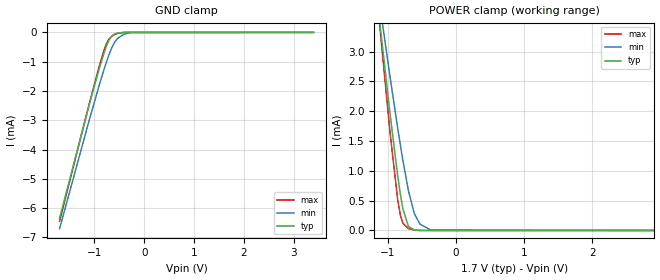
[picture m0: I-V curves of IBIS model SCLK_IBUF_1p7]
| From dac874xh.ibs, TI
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|   SCLK_IBUF_1p7 Model
[Model]   SCLK_IBUF_1p7
Model_type   Input
Vinl = 0.51
Vinh = 1.19
|   typ   min   max
C_comp   1.31128E-13  2.39925E-14  2.16304E-13
| Where nom  PVT is Nominal Process, 1.7V, 27C
|   Fast PVT is Strong Process,  1.701V, -40C
|   Slow PVT is Weak Process,   1.699V, 150C
[Model spec]
|subparameter
Vinl   0.51   0.5097   0.5103
Vinh   1.19   1.1893   1.1907
[Voltage Range]   1.7   1.699   1.701
[Temperature Range]   27   150   -40
[Power Clamp Reference]   1.7   1.699   1.701
[GND Clamp Reference]   0   0   0
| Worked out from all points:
|   GND clamp passes 1 mA (typ) near -0.86 V on its own axis
|   POWER clamp passes 1 mA (typ) near -0.87 V on its own axis
[GND Clamp]
|   Voltage   I(typ)   I(min)   I(max)
-1.7V     -6.346mA   -6.703mA   -6.448mA
-1.108V   -2.489mA   -3.012mA   -2.457mA
-909.5mV  -1.269mA   -1.833mA   -1.19mA
-802.4mV  -672.9uA   -1.237mA   -580uA
-761.6mV  -474.1uA   -1.023mA   -391.4uA
-710.6mV  -269.6uA   -773uA     -230.7uA
-649.4mV  -118.9uA   -512uA     -132.6uA
-593.3mV  -55.04uA   -328.8uA   -72.77uA
-527mV    -18.35uA   -191.5uA   -25.83uA
-399.5mV  -716.4nA   -56.52uA   -733.1nA
-272mV    0A         -5.142uA   0A
3.4V      0A         0A         0A
[POWER Clamp]
|   Voltage   I(typ)   I(min)   I(max)
-1.7V     9.733mA    8.663mA    10.85mA
-1.124V   3.512mA    3.807mA    3.46mA
-1.108V   3.353mA    3.682mA    3.272mA
-970.7mV  1.958mA    2.578mA    1.643mA
-858.5mV  921.5uA    1.719mA    518.9uA
-817.7mV  598.5uA    1.423mA    250.4uA
-782mV    362.4uA    1.175mA    123.4uA
-700.4mV  68.48uA    666.9uA    31.59uA
-613.7mV  7.599uA    281.7uA    4.809uA
-532.1mV  718.8nA    106.6uA    389.6nA
-368.9mV  0A         6.618uA    0A
3.4V      0A         0A         0A
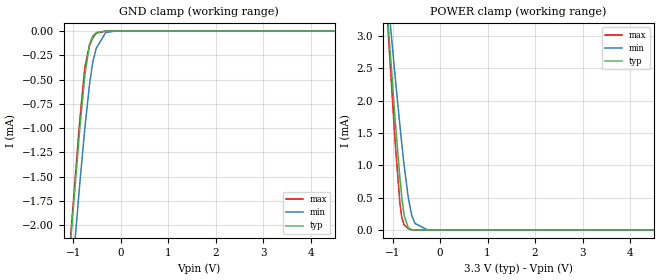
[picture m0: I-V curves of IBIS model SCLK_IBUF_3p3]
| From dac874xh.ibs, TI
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|   SCLK_IBUF_3p3 Model
[Model]   SCLK_IBUF_3p3
Model_type   Input
Vinl = 0.99
Vinh = 2.31
|   typ   min   max
C_comp   1.53747E-13  4.21027E-14   2.26743E-13
| Where nom  PVT is Nominal Process, 3.3V, 27C
|   Fast PVT is Strong Process,  3.6V, -40C
|   Slow PVT is Weak Process,   3.0V, 150C
[Model spec]
|subparameter
Vinl   0.99   0.9   1.08
Vinh   2.31   2.1   2.52
[Voltage Range]   3.3   3   3.6
[Temperature Range]   27   150   -40
[Power Clamp Reference]   3.3   3   3.6
[GND Clamp Reference]   0   0   0
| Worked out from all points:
|   GND clamp passes 1 mA (typ) near -0.86 V on its own axis
|   POWER clamp passes 1 mA (typ) near -0.87 V on its own axis
[GND Clamp]
|   Voltage   I(typ)   I(min)   I(max)
-3.3V     -17.09mA   -17mA      -17.62mA
-1.261V   -3.463mA   -3.945mA   -3.466mA
-1.112V   -2.513mA   -3.034mA   -2.481mA
-1.063V   -2.201mA   -2.735mA   -2.158mA
-864.6mV  -1.01mA    -1.578mA   -922uA
-755.7mV  -447.6uA   -992.9uA   -368uA
-656.7mV  -131.4uA   -540.2uA   -141.7uA
-587.4mV  -50.51uA   -313.3uA   -67.49uA
-518.1mV  -15.38uA   -178.2uA   -21.67uA
-320.1mV  -26.53nA   -15.29uA   -6.152nA
-122.1mV  0A         -65.56nA   0A
6.6V      0A         0A         0A
[POWER Clamp]
|   Voltage   I(typ)   I(min)   I(max)
-3.3V     27.55mA    22.59mA    32.03mA
-1.132V   3.598mA    3.874mA    3.561mA
-1.092V   3.186mA    3.551mA    3.075mA
-943.8mV  1.697mA    2.367mA    1.346mA
-844.8mV  808.1uA    1.619mA    415.2uA
-805.2mV  509.8uA    1.335mA    194.7uA
-755.7mV  227.9uA    1.001mA    77.89uA
-666.6mV  30.28uA    492.7uA    16.63uA
-597.3mV  4.805uA    233.2uA    3.064uA
-528mV    623.9nA    101.4uA    326.7nA
-260.7mV  0A         381.7nA    0A
6.6V      0A         0A         0A
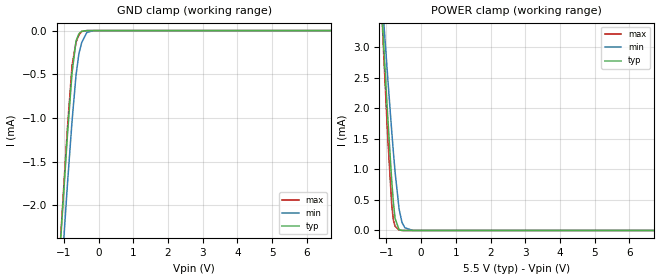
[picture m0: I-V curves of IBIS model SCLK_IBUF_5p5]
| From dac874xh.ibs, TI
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|   SCLK_IBUF_5p5 Model
[Model]   SCLK_IBUF_5p5
Model_type   Input
Vinl = 1.65
Vinh = 3.85
|   typ   min   max
C_comp   1.71923E-13  6.87543E-14   2.27606E-13
| Where nom  PVT is Nominal Process, 5.5V, 27C
|   Fast PVT is Strong Process,  5.501V, -40C
|   Slow PVT is Weak Process,   5.499V, 150C
[Model spec]
|subparameter
Vinl   1.65   1.6497   1.6503
Vinh   3.85   3.8493   3.8507
[Voltage Range]   5.5   5.499   5.501
[Temperature Range]   27   150   -40
[Power Clamp Reference]   5.5   5.499   5.501
[GND Clamp Reference]   0   0   0
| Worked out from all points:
|   GND clamp passes 1 mA (typ) near -0.86 V on its own axis
|   POWER clamp passes 1 mA (typ) near -0.87 V on its own axis
[GND Clamp]
|   Voltage   I(typ)   I(min)   I(max)
-5.5V     -32.01mA   -31.36mA   -33.19mA
-1.375V   -4.206mA   -4.655mA   -4.235mA
-1.161V   -2.82mA    -3.329mA   -2.8mA
-1.127V   -2.61mA    -3.128mA   -2.583mA
-896.5mV  -1.193mA   -1.759mA   -1.111mA
-764.5mV  -487.4uA   -1.038mA   -403.3uA
-649mV    -118.3uA   -510.5uA   -132.1uA
-566.5mV  -36.69uA   -263.8uA   -50.44uA
-484mV    -7.273uA   -134.4uA   -10.04uA
-335.5mV  -46.69nA   -20.7uA    -18.68nA
-137.5mV  0A         -99.89nA   0A
11V       0A         0A         0A
[POWER Clamp]
|   Voltage   I(typ)   I(min)   I(max)
-5.5V     53.23mA    46.94mA    61.4mA
-1.127V   3.552mA    3.838mA    3.507mA
-1.078V   3.039mA    3.435mA    2.902mA
-962.5mV  1.877mA    2.513mA    1.551mA
-847mV    826uA      1.635mA    431uA
-797.5mV  458.2uA    1.282mA    166.8uA
-748mV    195.9uA    951.5uA    68.73uA
-632.5mV  12.61uA    347.3uA    7.723uA
-550mV    1.201uA    132.7uA    694nA
-467.5mV  66.3nA     44.6uA     3.141nA
-236.5mV  0A         172.2nA    0A
11V       0A         0A         0A
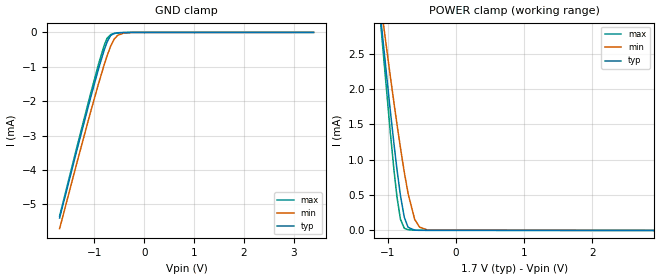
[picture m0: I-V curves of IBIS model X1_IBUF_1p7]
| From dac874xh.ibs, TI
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|   X1_IBUF_1p7 Model
[Model]   X1_IBUF_1p7
Model_type   Input
Vinl = 0.51
Vinh = 1.19
|   typ   min   max
C_comp   1.23493E-13  1.75877E-14  2.0538E-13
| Where nom  PVT is Nominal Process, 1.7V, 27C
|   Fast PVT is Strong Process,  1.701V, -40C
|   Slow PVT is Weak Process,   1.699V, 150C
[Model spec]
|subparameter
Vinl   0.51   0.5097   0.5103
Vinh   1.19   1.1893   1.1907
[Voltage Range]   1.7   1.699   1.701
[Temperature Range]   27   150   -40
[Power Clamp Reference]   1.7   1.699   1.701
[GND Clamp Reference]   0   0   0
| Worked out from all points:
|   GND clamp passes 1 mA (typ) near -0.91 V on its own axis
|   POWER clamp passes 1 mA (typ) near -0.89 V on its own axis
[GND Clamp]
|   Voltage   I(typ)   I(min)   I(max)
-1.7V     -5.397mA   -5.706mA   -5.341mA
-1.348V   -3.398mA   -3.766mA   -3.308mA
-1.088V   -1.956mA   -2.367mA   -1.839mA
-914.6mV  -1.04mA    -1.473mA   -904.3uA
-802.4mV  -503.5uA   -930.6uA   -368uA
-746.3mV  -279.2uA   -680.8uA   -170.9uA
-674.9mV  -90.32uA   -400.9uA   -64.49uA
-603.5mV  -26.85uA   -193.9uA   -33.21uA
-532.1mV  -10.75uA   -83.87uA   -16.98uA
-419.9mV  -3.161uA   -23.25uA   -6.524uA
-251.6mV  -219.8nA   -930.2nA   -740.5nA
3.4V      0A         0A         0A
[POWER Clamp]
|   Voltage   I(typ)   I(min)   I(max)
-1.7V     8.863mA    7.74mA     9.917mA
-1.103V   2.96mA     3.176mA    2.876mA
-965.6mV  1.685mA    2.176mA    1.376mA
-909.5mV  1.197mA    1.783mA    824.4uA
-868.7mV  864uA      1.505mA    474.2uA
-817.7mV  493uA      1.17mA     159.3uA
-761.6mV  188.7uA    826.4uA    32.12uA
-705.5mV  44.44uA    521.7uA    9.96uA
-608.6mV  4.018uA    156.6uA    3.561uA
-537.2mV  2.388uA    47.72uA    2.961uA
-419.9mV  2.111uA    5.817uA    2.749uA
3.4V      0A         0A         0A
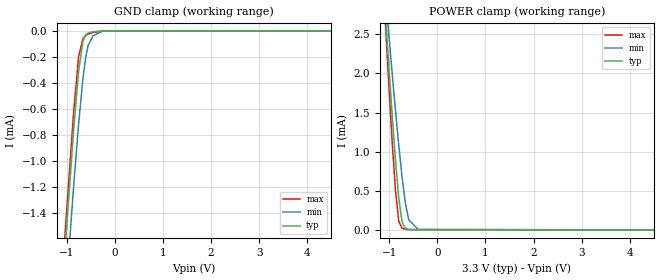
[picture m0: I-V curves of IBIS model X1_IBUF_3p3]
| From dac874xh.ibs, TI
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|   X1_IBUF_3p3 Model
[Model]   X1_IBUF_3p3
Model_type   Input
Vinl = 0.99
Vinh = 2.31
|   typ   min   max
C_comp   1.45567E-13  3.61244E-14  2.16097E-13
| Where nom  PVT is Nominal Process, 3.3V, 27C
|   Fast PVT is Strong Process,  3.6V, -40C
|   Slow PVT is Weak Process,   3.0V, 150C
[Model spec]
|subparameter
Vinl   0.99   0.9   1.08
Vinh   2.31   2.1   2.52
[Voltage Range]   3.3   3   3.6
[Temperature Range]   27   150   -40
[Power Clamp Reference]   3.3   3   3.6
[GND Clamp Reference]   0   0   0
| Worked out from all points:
|   GND clamp passes 1 mA (typ) near -0.91 V on its own axis
|   POWER clamp passes 1 mA (typ) near -0.89 V on its own axis
[GND Clamp]
|   Voltage   I(typ)   I(min)   I(max)
-3.3V     -14.67mA   -14.74mA   -14.82mA
-1.251V   -2.853mA   -3.237mA   -2.753mA
-1.102V   -2.034mA   -2.442mA   -1.918mA
-1.053V   -1.765mA   -2.182mA   -1.645mA
-854.7mV  -744.4uA   -1.178mA   -605.7uA
-755.7mV  -313.8uA   -721.2uA   -198.6uA
-666.6mV  -78.13uA   -372.3uA   -60.71uA
-607.2mV  -28.93uA   -202.2uA   -35.96uA
-557.7mV  -15.11uA   -113uA     -23.27uA
-458.7mV  -5.073uA   -37.2uA    -10.45uA
-260.7mV  -252.9nA   -1.163uA   -1.131uA
6.6V      0A         0A         0A
[POWER Clamp]
|   Voltage   I(typ)   I(min)   I(max)
-3.3V     25.22mA    20.41mA    29.39mA
-1.112V   3.046mA    3.242mA    2.978mA
-1.092V   2.857mA    3.096mA    2.755mA
-1.023V   2.208mA    2.589mA    1.987mA
-933.9mV  1.407mA    1.954mA    1.06mA
-874.5mV  911.3uA    1.545mA    522.5uA
-805.2mV  415uA      1.092mA    114.9uA
-735.9mV  104.4uA    681.7uA    20.01uA
-666.6mV  16uA       346.4uA    8.194uA
-597.3mV  5.054uA    132.1uA    5.848uA
-399.3mV  3.679uA    5.135uA    5.183uA
6.6V      0A         0A         0A
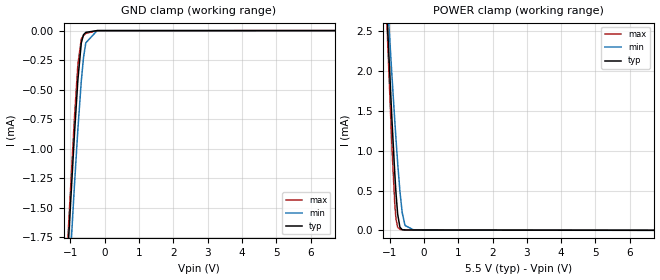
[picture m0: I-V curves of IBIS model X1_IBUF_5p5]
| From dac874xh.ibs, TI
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|   X1_IBUF_5p5 Model
[Model]   X1_IBUF_5p5
Model_type   Input
Vinl = 1.65
Vinh = 3.85
|   typ   min   max
C_comp   1.62855E-13   6.2518E-14  2.17306E-13
| Where nom  PVT is Nominal Process, 5.5V, 27C
|   Fast PVT is Strong Process,  5.501V, -40C
|   Slow PVT is Weak Process,   5.499V, 150C
[Model spec]
|subparameter
Vinl   1.65   1.6497   1.6503
Vinh   3.85   3.8493   3.8507
[Voltage Range]   5.5   5.499   5.501
[Temperature Range]   27   150   -40
[Power Clamp Reference]   5.5   5.499   5.501
[GND Clamp Reference]   0   0   0
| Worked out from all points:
|   GND clamp passes 1 mA (typ) near -0.91 V on its own axis
|   POWER clamp passes 1 mA (typ) near -0.89 V on its own axis
[GND Clamp]
|   Voltage   I(typ)   I(min)   I(max)
-5.5V     -27.53mA   -27.34mA   -28mA
-1.194V   -2.535mA   -2.929mA   -2.43mA
-1.161V   -2.353mA   -2.753mA   -2.245mA
-1.127V   -2.172mA   -2.577mA   -2.06mA
-1.045V   -1.724mA   -2.142mA   -1.603mA
-880mV    -867.7uA   -1.301mA   -730.4uA
-781mV    -413.6uA   -833.1uA   -285.3uA
-682mV    -104.1uA   -426.1uA   -72.27uA
-616mV    -34.11uA   -223.3uA   -40.77uA
-550mV    -15.09uA   -103.3uA   -24.18uA
-220mV    -164nA     -500.6nA   -1.039uA
11V       0A         0A         0A
[POWER Clamp]
|   Voltage   I(typ)   I(min)   I(max)
-5.5V     48.91mA    43.05mA    56.38mA
-1.127V   3.195mA    3.358mA    3.156mA
-1.095V   2.88mA     3.114mA    2.782mA
-929.5mV  1.371mA    1.925mA    1.019mA
-847mV    702.2uA    1.364mA    323.4uA
-814mV    472.6uA    1.15mA     149uA
-764.5mV  204.5uA    846.3uA    39.6uA
-698.5mV  40.02uA    490.4uA    13.82uA
-632.5mV  9.94uA     225.5uA    9.047uA
-550mV    6.26uA     62.42uA    7.93uA
-286mV    5.751uA    4.563uA    7.496uA
11V       0A         0A         0A
